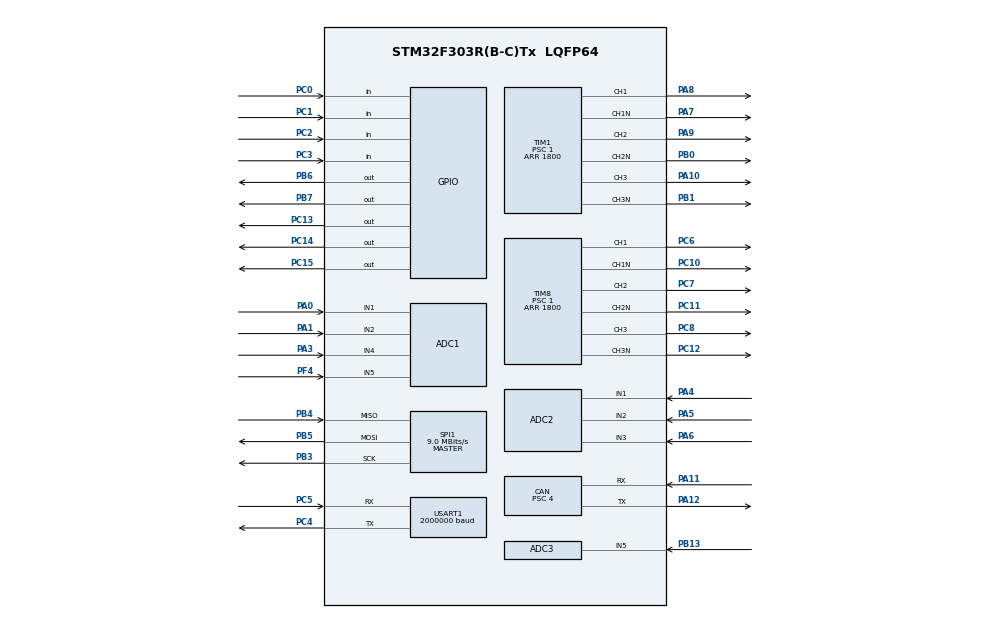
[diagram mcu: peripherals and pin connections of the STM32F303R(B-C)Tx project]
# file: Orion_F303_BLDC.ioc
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ADC1.Channel-9\#ChannelRegularConversion=ADC_CHANNEL_1
ADC1.ClockPrescaler=ADC_CLOCK_SYNC_PCLK_DIV2
ADC1.InjNumberOfConversion=4
ADC1.InjectedChannel-13\#ChannelInjectedConversion=ADC_CHANNEL_1
ADC1.InjectedChannel-14\#ChannelInjectedConversion=ADC_CHANNEL_4
ADC1.InjectedChannel-15\#ChannelInjectedConversion=ADC_CHANNEL_5
ADC1.InjectedChannel-16\#ChannelInjectedConversion=ADC_CHANNEL_2
ADC1.InjectedOffset-13\#ChannelInjectedConversion=0
ADC1.InjectedOffset-14\#ChannelInjectedConversion=0
ADC1.InjectedOffset-15\#ChannelInjectedConversion=0
ADC1.InjectedOffset-16\#ChannelInjectedConversion=0
ADC1.InjectedOffsetNumber-13\#ChannelInjectedConversion=ADC_OFFSET_NONE
ADC1.InjectedOffsetNumber-14\#ChannelInjectedConversion=ADC_OFFSET_NONE
ADC1.InjectedOffsetNumber-15\#ChannelInjectedConversion=ADC_OFFSET_NONE
ADC1.InjectedOffsetNumber-16\#ChannelInjectedConversion=ADC_OFFSET_NONE
ADC1.InjectedRank-13\#ChannelInjectedConversion=1
ADC1.InjectedRank-14\#ChannelInjectedConversion=2
ADC1.InjectedRank-15\#ChannelInjectedConversion=3
ADC1.InjectedRank-16\#ChannelInjectedConversion=4
ADC1.InjectedSamplingTime-13\#ChannelInjectedConversion=ADC_SAMPLETIME_61CYCLES_5
ADC1.InjectedSamplingTime-14\#ChannelInjectedConversion=ADC_SAMPLETIME_61CYCLES_5
ADC1.InjectedSamplingTime-15\#ChannelInjectedConversion=ADC_SAMPLETIME_61CYCLES_5
ADC1.InjectedSamplingTime-16\#ChannelInjectedConversion=ADC_SAMPLETIME_61CYCLES_5
ADC1.InjectedSamplingTimeOPAMP-13\#ChannelInjectedConversion=ADC_SAMPLETIME_61CYCLES_5
ADC1.InjectedSamplingTimeOPAMP-14\#ChannelInjectedConversion=ADC_SAMPLETIME_61CYCLES_5
ADC1.InjectedSamplingTimeOPAMP-15\#ChannelInjectedConversion=ADC_SAMPLETIME_61CYCLES_5
ADC1.InjectedSamplingTimeOPAMP-16\#ChannelInjectedConversion=ADC_SAMPLETIME_19CYCLES_5
ADC1.NbrOfConversion=1
ADC1.NbrOfConversionFlag=1
ADC1.Offset-9\#ChannelRegularConversion=0
ADC1.OffsetNumber-9\#ChannelRegularConversion=ADC_OFFSET_NONE
ADC1.Rank-9\#ChannelRegularConversion=1
ADC1.Rank4_Channel=ADC_CHANNEL_2
ADC1.SamplingTime-9\#ChannelRegularConversion=ADC_SAMPLETIME_61CYCLES_5
ADC1.master=1
ADC2.Channel-2\#ChannelRegularConversion=ADC_CHANNEL_1
ADC2.ClockPrescaler=ADC_CLOCK_SYNC_PCLK_DIV2
ADC2.InjNumberOfConversion=3
ADC2.InjectedChannel-4\#ChannelInjectedConversion=ADC_CHANNEL_1
ADC2.InjectedChannel-5\#ChannelInjectedConversion=ADC_CHANNEL_2
ADC2.InjectedChannel-6\#ChannelInjectedConversion=ADC_CHANNEL_3
ADC2.InjectedOffset-4\#ChannelInjectedConversion=0
ADC2.InjectedOffset-5\#ChannelInjectedConversion=0
ADC2.InjectedOffset-6\#ChannelInjectedConversion=0
ADC2.InjectedOffsetNumber-4\#ChannelInjectedConversion=ADC_OFFSET_NONE
ADC2.InjectedOffsetNumber-5\#ChannelInjectedConversion=ADC_OFFSET_NONE
ADC2.InjectedOffsetNumber-6\#ChannelInjectedConversion=ADC_OFFSET_NONE
ADC2.InjectedRank-4\#ChannelInjectedConversion=1
ADC2.InjectedRank-5\#ChannelInjectedConversion=2
ADC2.InjectedRank-6\#ChannelInjectedConversion=3
ADC2.InjectedSamplingTime-4\#ChannelInjectedConversion=ADC_SAMPLETIME_61CYCLES_5
ADC2.InjectedSamplingTime-5\#ChannelInjectedConversion=ADC_SAMPLETIME_61CYCLES_5
ADC2.InjectedSamplingTime-6\#ChannelInjectedConversion=ADC_SAMPLETIME_61CYCLES_5
ADC2.InjectedSamplingTimeOPAMP-4\#ChannelInjectedConversion=ADC_SAMPLETIME_61CYCLES_5
ADC2.InjectedSamplingTimeOPAMP-5\#ChannelInjectedConversion=ADC_SAMPLETIME_19CYCLES_5
ADC2.InjectedSamplingTimeOPAMP-6\#ChannelInjectedConversion=ADC_SAMPLETIME_19CYCLES_5
ADC2.NbrOfConversion=1
ADC2.NbrOfConversionFlag=1
ADC2.Offset-2\#ChannelRegularConversion=0
ADC2.OffsetNumber-2\#ChannelRegularConversion=ADC_OFFSET_NONE
ADC2.Rank-2\#ChannelRegularConversion=1
ADC2.Rank2_Channel=ADC_CHANNEL_2
ADC2.Rank3_Channel=ADC_CHANNEL_3
ADC2.SamplingTime-2\#ChannelRegularConversion=ADC_SAMPLETIME_1CYCLE_5
ADC3.Channel-6\#ChannelRegularConversion=ADC_CHANNEL_5
ADC3.InjNumberOfConversion=1
ADC3.InjectedChannel-7\#ChannelInjectedConversion=ADC_CHANNEL_5
ADC3.InjectedOffset-7\#ChannelInjectedConversion=0
ADC3.InjectedOffsetNumber-7\#ChannelInjectedConversion=ADC_OFFSET_NONE
ADC3.InjectedRank-7\#ChannelInjectedConversion=1
ADC3.InjectedSamplingTime-7\#ChannelInjectedConversion=ADC_SAMPLETIME_61CYCLES_5
ADC3.InjectedSamplingTimeOPAMP-7\#ChannelInjectedConversion=ADC_SAMPLETIME_61CYCLES_5
ADC3.NbrOfConversion=1
ADC3.NbrOfConversionFlag=1
ADC3.Offset-6\#ChannelRegularConversion=0
ADC3.OffsetNumber-6\#ChannelRegularConversion=ADC_OFFSET_NONE
ADC3.Rank-6\#ChannelRegularConversion=1
ADC3.Rank1_Channel=ADC_CHANNEL_5
ADC3.Rank2_Channel=ADC_CHANNEL_5
ADC3.Rank3_Channel=ADC_CHANNEL_5
ADC3.SamplingTime-6\#ChannelRegularConversion=ADC_SAMPLETIME_61CYCLES_5
ADC3.SamplingTimeOPAMP-6\#ChannelRegularConversion=ADC_SAMPLETIME_61CYCLES_5
ADC3.master=1
CAN.BS1=CAN_BS1_4TQ
CAN.BS2=CAN_BS2_4TQ
CAN.CalculateBaudRate=1000000
CAN.CalculateTimeBit=1000
CAN.CalculateTimeQuantum=111.11111111111111
CAN.NART=ENABLE
CAN.Prescaler=4
CAN.SJW=CAN_SJW_1TQ
Dma.Request0=USART1_TX
Dma.USART1_TX.0.Direction=DMA_MEMORY_TO_PERIPH
Dma.USART1_TX.0.Instance=DMA1_Channel4
Dma.USART1_TX.0.MemDataAlignment=DMA_MDATAALIGN_BYTE
Dma.USART1_TX.0.MemInc=DMA_MINC_ENABLE
Dma.USART1_TX.0.Mode=DMA_NORMAL
Dma.USART1_TX.0.PeriphDataAlignment=DMA_PDATAALIGN_BYTE
Dma.USART1_TX.0.PeriphInc=DMA_PINC_DISABLE
Dma.USART1_TX.0.Priority=DMA_PRIORITY_LOW
Mcu.Family=STM32F3
Mcu.Name=STM32F303R(B-C)Tx
Mcu.Package=LQFP64
NVIC.CAN_RX1_IRQn=true\:2\:0\:true\:false\:true\:true\:true\:true
NVIC.DMA1_Channel4_IRQn=true\:14\:0\:true\:false\:true\:false\:true\:true
NVIC.PriorityGroup=NVIC_PRIORITYGROUP_4
NVIC.TIM1_CC_IRQn=true\:1\:0\:true\:false\:true\:true\:true\:true
NVIC.TIM1_UP_TIM16_IRQn=true\:1\:0\:true\:false\:true\:true\:true\:true
NVIC.TIM8_CC_IRQn=true\:2\:0\:true\:false\:true\:true\:true\:true
NVIC.TIM8_UP_IRQn=true\:2\:0\:true\:false\:true\:true\:true\:true
NVIC.USART1_IRQn=true\:15\:0\:true\:false\:true\:true\:true\:true
PA0.Mode=IN1-Single-Ended
PA0.Signal=ADC1_IN1
PA1.Mode=IN2-Single-Ended
PA1.Signal=ADC1_IN2
PA10.Signal=S_TIM1_CH3
PA11.Mode=CAN_Activate
PA11.Signal=CAN_RX
PA12.Mode=CAN_Activate
PA12.Signal=CAN_TX
PA13.Mode=Serial_Wire
PA13.Signal=SYS_JTMS-SWDIO
PA14.Mode=Serial_Wire
PA14.Signal=SYS_JTCK-SWCLK
PA3.Mode=IN4-Single-Ended
PA3.Signal=ADC1_IN4
PA4.Mode=IN1-Single-Ended
PA4.Signal=ADC2_IN1
PA5.Mode=IN2-Single-Ended
PA5.Signal=ADC2_IN2
PA6.Mode=IN3-Single-Ended
PA6.Signal=ADC2_IN3
PA7.Mode=PWM Generation1 CH1 CH1N
PA7.Signal=TIM1_CH1N
PA8.Signal=S_TIM1_CH1
PA9.Signal=S_TIM1_CH2
PB0.Mode=PWM Generation2 CH2 CH2N
PB0.Signal=TIM1_CH2N
PB1.Mode=PWM Generation3 CH3 CH3N
PB1.Signal=TIM1_CH3N
PB13.Mode=IN5-Single-Ended
PB13.Signal=ADC3_IN5
PB3.Mode=Full_Duplex_Master
PB3.Signal=SPI1_SCK
PB4.GPIO_PuPd=GPIO_PULLDOWN
PB4.Mode=Full_Duplex_Master
PB4.Signal=SPI1_MISO
PB5.Mode=Full_Duplex_Master
PB5.Signal=SPI1_MOSI
PB6.Signal=GPIO_Output
PB7.Signal=GPIO_Output
PC0.GPIO_PuPd=GPIO_PULLUP
PC0.Signal=GPIO_Input
PC1.GPIO_PuPd=GPIO_PULLUP
PC1.Signal=GPIO_Input
PC10.Mode=PWM Generation1 CH1 CH1N
PC10.Signal=TIM8_CH1N
PC11.Mode=PWM Generation2 CH2 CH2N
PC11.Signal=TIM8_CH2N
PC12.Mode=PWM Generation3 CH3 CH3N
PC12.Signal=TIM8_CH3N
PC13.Signal=GPIO_Output
PC14-OSC32_IN.Signal=GPIO_Output
PC15-OSC32_OUT.Signal=GPIO_Output
PC2.GPIO_PuPd=GPIO_PULLUP
PC2.Signal=GPIO_Input
PC3.GPIO_PuPd=GPIO_PULLUP
PC3.Signal=GPIO_Input
PC4.Mode=Asynchronous
PC4.Signal=USART1_TX
PC5.GPIO_PuPd=GPIO_PULLUP
PC5.Mode=Asynchronous
PC5.Signal=USART1_RX
PC6.Signal=S_TIM8_CH1
PC7.Signal=S_TIM8_CH2
PC8.Signal=S_TIM8_CH3
PF0-OSC_IN.Mode=HSE-External-Oscillator
PF0-OSC_IN.Signal=RCC_OSC_IN
PF1-OSC_OUT.Mode=HSE-External-Oscillator
PF1-OSC_OUT.Signal=RCC_OSC_OUT
PF4.Mode=IN5-Single-Ended
PF4.Signal=ADC1_IN5
ProjectManager.HeapSize=0x200
ProjectManager.StackSize=0x400
ProjectManager.TargetToolchain=STM32CubeIDE
RCC.AHBFreq_Value=72000000
RCC.APB1CLKDivider=RCC_HCLK_DIV2
RCC.APB1Freq_Value=36000000
RCC.APB1TimFreq_Value=72000000
RCC.APB2CLKDivider=RCC_HCLK_DIV2
RCC.APB2Freq_Value=36000000
RCC.APB2TimFreq_Value=72000000
RCC.CortexFreq_Value=72000000
RCC.HCLKFreq_Value=72000000
RCC.HSE_VALUE=8000000
RCC.HSI_VALUE=8000000
RCC.LSE_VALUE=32768
RCC.PLLMUL=RCC_PLL_MUL9
RCC.PLLSourceVirtual=RCC_PLLSOURCE_HSE
RCC.SYSCLKFreq_VALUE=72000000
RCC.SYSCLKSourceVirtual=RCC_SYSCLKSOURCE_PLLCLK
RCC.USBFreq_Value=72000000
SH.S_TIM1_CH1.0=TIM1_CH1,PWM Generation1 CH1 CH1N
SH.S_TIM1_CH2.0=TIM1_CH2,PWM Generation2 CH2 CH2N
SH.S_TIM1_CH3.0=TIM1_CH3,PWM Generation3 CH3 CH3N
SH.S_TIM8_CH1.0=TIM8_CH1,PWM Generation1 CH1 CH1N
SH.S_TIM8_CH2.0=TIM8_CH2,PWM Generation2 CH2 CH2N
SH.S_TIM8_CH3.0=TIM8_CH3,PWM Generation3 CH3 CH3N
SPI1.BaudRatePrescaler=SPI_BAUDRATEPRESCALER_4
SPI1.CLKPhase=SPI_PHASE_2EDGE
SPI1.CLKPolarity=SPI_POLARITY_HIGH
SPI1.CalculateBaudRate=9.0 MBits/s
SPI1.DataSize=SPI_DATASIZE_8BIT
SPI1.Direction=SPI_DIRECTION_2LINES
SPI1.Mode=SPI_MODE_MASTER
SPI1.VirtualType=VM_MASTER
TIM1.AutomaticOutput=TIM_AUTOMATICOUTPUT_DISABLE
TIM1.Channel-PWM\ Generation1\ CH1\ CH1N=TIM_CHANNEL_1
TIM1.Channel-PWM\ Generation2\ CH2\ CH2N=TIM_CHANNEL_2
TIM1.Channel-PWM\ Generation3\ CH3\ CH3N=TIM_CHANNEL_3
TIM1.DeadTime=10
TIM1.OCMode_PWM-PWM\ Generation1\ CH1\ CH1N=TIM_OCMODE_PWM1
TIM1.OCMode_PWM-PWM\ Generation2\ CH2\ CH2N=TIM_OCMODE_PWM1
TIM1.OCMode_PWM-PWM\ Generation3\ CH3\ CH3N=TIM_OCMODE_PWM1
TIM1.Period=1800
TIM1.Prescaler=1
TIM1.TIM_MasterOutputTrigger=TIM_TRGO_OC4REF
TIM1.TIM_MasterOutputTrigger2=TIM_TRGO2_UPDATE
TIM1.TIM_MasterSlaveMode=TIM_MASTERSLAVEMODE_ENABLE
TIM8.AutomaticOutput=TIM_AUTOMATICOUTPUT_DISABLE
TIM8.Break2Filter=4
TIM8.BreakFilter=4
TIM8.BreakState=TIM_BREAK_DISABLE
TIM8.Channel-PWM\ Generation1\ CH1\ CH1N=TIM_CHANNEL_1
TIM8.Channel-PWM\ Generation2\ CH2\ CH2N=TIM_CHANNEL_2
TIM8.Channel-PWM\ Generation3\ CH3\ CH3N=TIM_CHANNEL_3
TIM8.DeadTime=10
TIM8.OCMode_PWM-PWM\ Generation1\ CH1\ CH1N=TIM_OCMODE_PWM1
TIM8.OCMode_PWM-PWM\ Generation2\ CH2\ CH2N=TIM_OCMODE_PWM1
TIM8.OCMode_PWM-PWM\ Generation3\ CH3\ CH3N=TIM_OCMODE_PWM1
TIM8.Period=1800
TIM8.Prescaler=1
TIM8.TIM_MasterOutputTrigger=TIM_TRGO_OC4REF
TIM8.TIM_MasterOutputTrigger2=TIM_TRGO2_UPDATE
TIM8.TIM_MasterSlaveMode=TIM_MASTERSLAVEMODE_ENABLE
USART1.BaudRate=2000000
USART1.VirtualMode-Asynchronous=VM_ASYNC
board=custom

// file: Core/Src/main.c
/* USER CODE BEGIN Header */
/**
 ******************************************************************************
 * @file           : main.c
 * @brief          : Main program body
 * @note           : Dual BLDC control application. This file owns mode control,
 *                   safety management, and high-level scheduling.
 ******************************************************************************
 * @attention
 *
 * Copyright (c) 2022 STMicroelectronics.
 * All rights reserved.
 *
 * This software is licensed under terms that can be found in the LICENSE file
 * in the root directory of this software component.
 * If no LICENSE file comes with this software, it is provided AS-IS.
 *
 ******************************************************************************
 */
/* USER CODE END Header */
#include "main.h"

#include "adc.h"
#include "calibration.h"
#include "can.h"
#include "comms.h"
#include "control_limits.h"
#include "control_mode.h"
#include "diagnostics.h"
#include "dma.h"
#include "foc_control.h"
#include "foc_diagnostic.h"
#include "gpio.h"
#include "protect.h"
#include "spi.h"
#include "startup_sequence.h"
#include "tim.h"
#include "usart.h"

/* USER CODE BEGIN Includes */
#include <math.h>
#include <stdarg.h>
#include <stdbool.h>
#include <stdint.h>
#include <stdio.h>
#include <stdlib.h>
#include <string.h>

#include "flash.h"
#include "fw_version.h"
#include "motor.h"
#include "stm32f3xx_hal.h"
/* USER CODE END Includes */

/* USER CODE BEGIN PV */

const fw_version_t g_fw_version __attribute__((section(".fw_version"), used)) = {FW_VERSION_MAGIC, 0U};

/* USER CODE END PV */

void SystemClock_Config(void);
/* USER CODE BEGIN PFP */
void runMode(void);

/* USER CODE END PFP */

/* USER CODE BEGIN 0 */
// 0 ~ M_PI*2 * 4

motor_control_cmd_t cmd[2];
calib_point_t calib[2];
enc_offset_t enc_offset[2];
motor_real_t motor_real[2];
motor_param_t motor_param[2];
motor_pid_control_t pid[2];

error_t error;
system_t sys;
enc_error_watcher_t enc_error_watcher;
calib_process_t calib_process;

static inline void updateMotorSpeedEstimate(void)
{
  for (int i = 0; i < 2; i++) {
    int ret = calcMotorSpeed(&motor_real[i], &mt6835[i], &sys, &enc_error_watcher);
    if (ret < 0) {
      p("stop!! speed error");
    }
  }
}

inline void motorProcess_itr(bool motor)
{
  updateADC(motor);
  updateMT6835(motor);
  focControlApplyVoltage(motor, cmd[motor].out_v_final, cmd[motor].speed, motor_param[motor].output_voltage_limit);
}

// TIM1 HCLK 96MHz / 2 prescaler / 1600 cnt -> 30kHz interrupt -> 1ms cycle
#define INTERRUPT_KHZ_1MS (30)
volatile uint32_t interrupt_timer_cnt = 0, main_loop_remain_counter = 0;
volatile uint32_t system_exec_time_stamp[10] = {0};

static inline void waitForNextMainCycle(void)
{
  main_loop_remain_counter = INTERRUPT_KHZ_1MS - interrupt_timer_cnt;
  while (interrupt_timer_cnt <= INTERRUPT_KHZ_1MS);
  interrupt_timer_cnt = 0;
}

void HAL_TIM_PeriodElapsedCallback(TIM_HandleTypeDef * htim)
{
  // TIM1 : M1
  // TIM8 : M0
  static bool motor_select_toggle = false;
  interrupt_timer_cnt++;
  motor_select_toggle = !motor_select_toggle;

  if (sys.is_starting_mode) {
    updateADC(motor_select_toggle);
    return;
  }

  setLedBlue(false);
  if (isEncoderCalibrationActive()) {
    calibrationProcess_itr(motor_select_toggle);
  } else if (isMotorCalibrationActive()) {
    motorCalibrationProcess_itr(motor_select_toggle);
  } else if (isFocDiagnosticActive()) {
    focDiagnosticProcess_itr(motor_select_toggle);
  } else {
    motorProcess_itr(motor_select_toggle);
  }

  setLedBlue(true);
  sys.task_complete_timer_cnt = htim->Instance->CNT;
}

void waitPowerOnTimeout()
{
  p("reset!!!");
  while (sys.power_enable_cnt > 0) {
    sys.power_enable_cnt--;
    sendCanData();
    sendError(error.id, error.info, error.value);
    HAL_Delay(2);
  }
  HAL_Delay(2);
  HAL_NVIC_SystemReset();
}

// 1KHz
void runMode(void)
{
  if (sys.free_wheel_cnt > 0) {
    sys.free_wheel_cnt--;
    if (sys.free_wheel_cnt == 0) {
      resumePwmOutput();
    }
  }
  system_exec_time_stamp[1] = interrupt_timer_cnt;

  if (sys.manual_offset_radian > M_PI * 2) {
    sys.manual_offset_radian = 0;
  }

  //- 0.5 max spd 0.75
  //+ 3.45 max spd 3.25
  // Manual test by switches may override speed command.
  // Used for quick standalone checks without CAN.
  for (int i = 0; i < 2; i++) {
    if (isPushedSW1()) {
      cmd[i].speed = SPEED_CMD_LIMIT_RPS;
    } else if (isPushedSW2()) {
      cmd[i].speed = -SPEED_CMD_LIMIT_RPS;
    } else if (isPushedSW3()) {
      cmd[i].speed = SPEED_CMD_LIMIT_RPS;
      //resumePwmOutput();
    } else if (isPushedSW4()) {
      cmd[i].speed = -SPEED_CMD_LIMIT_RPS;
      //setPwmOutPutFreeWheel();
    }

    speedToOutputVoltage(&pid[i], &motor_real[i], &motor_param[i], &cmd[i]);

    // Output Voltage Override
    if (cmd[i].timeout_cnt > 0) {
      cmd[i].timeout_cnt--;
    }

    if (cmd[i].timeout_cnt == 0) {
      cmd[i].out_v = 0;
    }

    if (sys.free_wheel_cnt > 0) {
      cmd[i].out_v = 0;
    }
  }

  system_exec_time_stamp[2] = interrupt_timer_cnt;
  for (int i = 0; i < 2; i++) {
    cmd[i].out_v_final = cmd[i].out_v;
  }

  system_exec_time_stamp[3] = interrupt_timer_cnt;
  printRuntimeDiagnostics();

  if (cmd[0].speed == 0 && cmd[1].speed == 0) {
    sys.zero_output_sleep_cnt++;
    if (sys.zero_output_sleep_cnt > 5000) {
      setPwmOutPutFreeWheel();
    }
  } else {
    if (sys.zero_output_sleep_cnt != 0) {
      resumePwmOutput();
    }
    sys.zero_output_sleep_cnt = 0;
  }
}

/* USER CODE END 0 */

int main(void)
{

  /* MCU Configuration--------------------------------------------------------*/

  /* Reset of all peripherals, Initializes the Flash interface and the Systick. */
  HAL_Init();

  /* Configure the system clock */
  SystemClock_Config();

  /* Initialize all configured peripherals */
  MX_GPIO_Init();
  MX_DMA_Init();
  MX_ADC1_Init();
  MX_ADC2_Init();
  MX_ADC3_Init();
  MX_CAN_Init();
  MX_SPI1_Init();
  MX_TIM1_Init();
  MX_TIM8_Init();
  MX_USART1_UART_Init();
  /* USER CODE BEGIN 2 */
  runStartupSequence();

  /* USER CODE END 2 */

  /* Infinite loop */
  while (1) {

    /* USER CODE BEGIN 3 */
    receiveUserSerialCommand();

    updateMotorSpeedEstimate();
    adcUpdateTemperatureFilters();
    sendCanData();

    system_exec_time_stamp[0] = interrupt_timer_cnt;
    runControlMode();
    protect();

    setLedRed(true);

    // Wait until next 1ms cycle.
    // Expected idle/load split is roughly balanced in nominal case.
    waitForNextMainCycle();

    setLedRed(false);
  }
  /* USER CODE END 3 */
}

void SystemClock_Config(void)
{
  RCC_OscInitTypeDef RCC_OscInitStruct = {0};
  RCC_ClkInitTypeDef RCC_ClkInitStruct = {0};
  RCC_PeriphCLKInitTypeDef PeriphClkInit = {0};

  /** Initializes the RCC Oscillators according to the specified parameters
  * in the RCC_OscInitTypeDef structure.
  */
  RCC_OscInitStruct.OscillatorType = RCC_OSCILLATORTYPE_HSE;
  RCC_OscInitStruct.HSEState = RCC_HSE_ON;
  RCC_OscInitStruct.HSEPredivValue = RCC_HSE_PREDIV_DIV1;
  RCC_OscInitStruct.HSIState = RCC_HSI_ON;
  RCC_OscInitStruct.PLL.PLLState = RCC_PLL_ON;
  RCC_OscInitStruct.PLL.PLLSource = RCC_PLLSOURCE_HSE;
  RCC_OscInitStruct.PLL.PLLMUL = RCC_PLL_MUL12;
  if (HAL_RCC_OscConfig(&RCC_OscInitStruct) != HAL_OK) {
    Error_Handler();
  }

  /** Initializes the CPU, AHB and APB buses clocks
  */
  RCC_ClkInitStruct.ClockType = RCC_CLOCKTYPE_HCLK | RCC_CLOCKTYPE_SYSCLK | RCC_CLOCKTYPE_PCLK1 | RCC_CLOCKTYPE_PCLK2;
  RCC_ClkInitStruct.SYSCLKSource = RCC_SYSCLKSOURCE_PLLCLK;
  RCC_ClkInitStruct.AHBCLKDivider = RCC_SYSCLK_DIV1;
  RCC_ClkInitStruct.APB1CLKDivider = RCC_HCLK_DIV4;
  RCC_ClkInitStruct.APB2CLKDivider = RCC_HCLK_DIV2;

  if (HAL_RCC_ClockConfig(&RCC_ClkInitStruct, FLASH_LATENCY_2) != HAL_OK) {
    Error_Handler();
  }
  PeriphClkInit.PeriphClockSelection = RCC_PERIPHCLK_USART1 | RCC_PERIPHCLK_TIM1 | RCC_PERIPHCLK_TIM8 | RCC_PERIPHCLK_ADC34;
  PeriphClkInit.Usart1ClockSelection = RCC_USART1CLKSOURCE_PCLK2;
  PeriphClkInit.Adc34ClockSelection = RCC_ADC34PLLCLK_DIV2;
  PeriphClkInit.Tim1ClockSelection = RCC_TIM1CLK_HCLK;
  PeriphClkInit.Tim8ClockSelection = RCC_TIM8CLK_HCLK;
  if (HAL_RCCEx_PeriphCLKConfig(&PeriphClkInit) != HAL_OK) {
    Error_Handler();
  }
}

void Error_Handler(void)
{
  /* USER CODE BEGIN Error_Handler_Debug */
  /* User can add his own implementation to report the HAL error return state */
  __disable_irq();
  forceStopAllPwmOutputAndTimer();
  while (1) {
  }
  /* USER CODE END Error_Handler_Debug */
}
